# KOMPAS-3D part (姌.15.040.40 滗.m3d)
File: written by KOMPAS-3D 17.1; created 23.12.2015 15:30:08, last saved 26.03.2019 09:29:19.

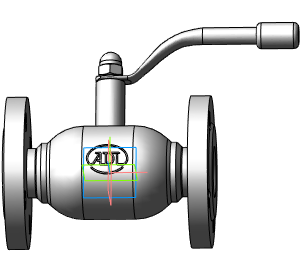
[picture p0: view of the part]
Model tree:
1. Операция без истории:4  (labels: Сталь 20  ГОСТ 1050-88)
